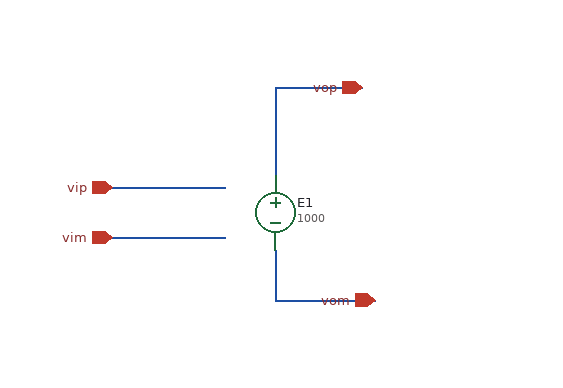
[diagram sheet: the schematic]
v {xschem version=3.4.8RC file_version=1.2}
G {}
K {}
V {}
S {}
E {}
N 1230 -640 1320 -640 {lab=vip}
N 1230 -600 1320 -600 {lab=vim}
N 1360 -720 1430 -720 {lab=vop}
N 1360 -720 1360 -650 {lab=vop}
N 1360 -550 1440 -550 {lab=vom}
N 1360 -590 1360 -550 {lab=vom}
C {vcvs.sym} 1360 -620 0 0 {name=E1 value=1000}
C {iopin.sym} 1430 -720 0 0 {name=p1 lab=vop}
C {iopin.sym} 1440 -550 0 0 {name=p2 lab=vom}
C {iopin.sym} 1230 -600 2 0 {name=p3 lab=vim}
C {iopin.sym} 1230 -640 2 0 {name=p4 lab=vip
}
